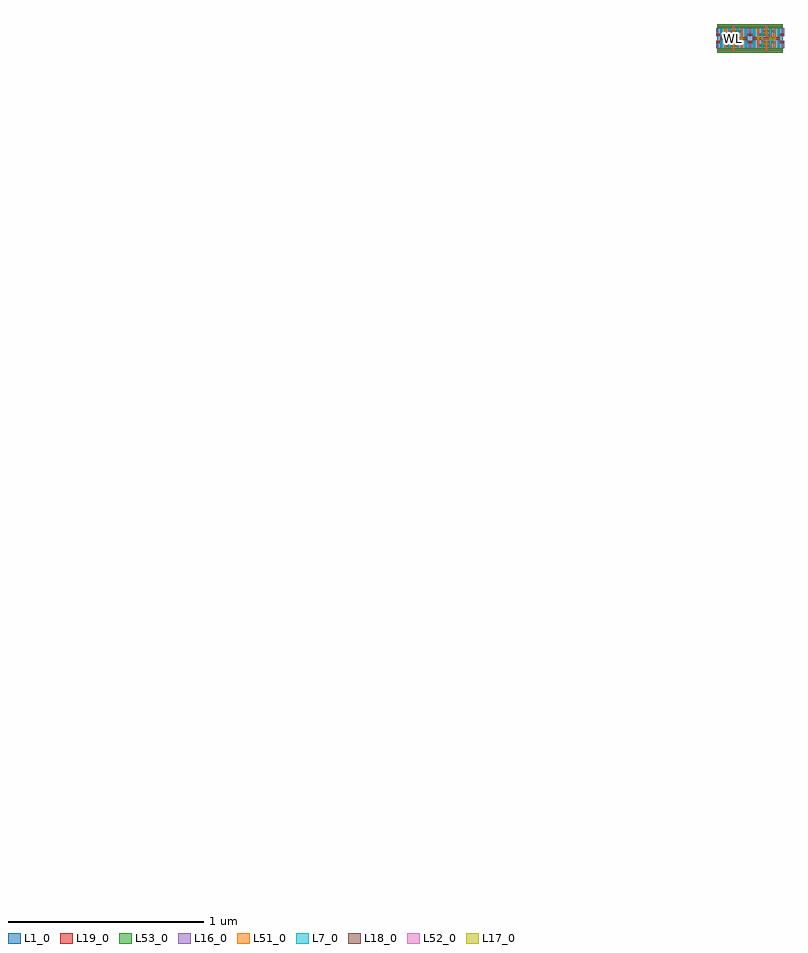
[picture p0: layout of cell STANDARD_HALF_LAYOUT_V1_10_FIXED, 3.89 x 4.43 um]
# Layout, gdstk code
import gdstk
lib = gdstk.Library(unit=1e-6, precision=1e-09)
def R(c, l, rs):  # rectangles x0, y0, x1, y1
    for r in rs: c.add(gdstk.rectangle(r[:2], r[2:], *l))
def A(c, l, x, y, w, h, nx, ny, dx, dy):  # array of equal rectangles
    R(c, l, [(x+i*dx, y+j*dy, x+i*dx+w, y+j*dy+h) for i in range(nx) for j in range(ny)])
def P(c, l, *ps):  # polygons
    for p in ps: c.add(gdstk.Polygon(p, *l))
L1_0 = (1, 0)
L7_0 = (7, 0)
L16_0 = (16, 0)
L17_0 = (17, 0)
L18_0 = (18, 0)
L19_0 = (19, 0)
L51_0 = (51, 0)
L52_0 = (52, 0)
L53_0 = (53, 0)

standard_half_layout_v1_ = lib.new_cell('STANDARD_HALF_LAYOUT_V1_10_FIXED')
A(standard_half_layout_v1_, L1_0, 0, 0, 0.042, 0.062, 8, 2, 0.042, 0.062)
P(standard_half_layout_v1_, L1_0, [(-2.637,-3.867),(-2.637,-3.867),(-2.637,-3.867),(-2.637,-3.867)],
  [(-3.548,-4.293),(-3.548,-4.293),(-3.548,-4.293),(-3.548,-4.293)],
  [(0.151,-0.013),(0.151,-0.013),(0.151,-0.013),(0.151,-0.013)],
  [(0.017,0.137),(0.017,0.137),(0.017,0.137),(0.017,0.137)],
  [(0.319,-0.013),(0.319,-0.013),(0.319,-0.013),(0.319,-0.013)],
  [(0.185,0.137),(0.185,0.137),(0.185,0.137),(0.185,0.137)])
A(standard_half_layout_v1_, L7_0, 0.015, 0.011, 0.012, 0.04, 8, 2, 0.042, 0.062)
A(standard_half_layout_v1_, L16_0, 0.015, 0.011, 0.012, 0.057, 3, 1, 0.021, 0)
A(standard_half_layout_v1_, L16_0, 0.183, 0.011, 0.012, 0.057, 3, 1, 0.021, 0)
A(standard_half_layout_v1_, L16_0, 0.099, 0.056, 0.012, 0.057, 3, 1, 0.021, 0)
A(standard_half_layout_v1_, L16_0, 0.267, 0.056, 0.012, 0.057, 3, 1, 0.021, 0)
R(standard_half_layout_v1_, L16_0, [(0.078,-0.006,0.09,0.051), (0.246,-0.006,0.258,0.051), (-0.006,0.011,0.006,0.051), (0.099,0.011,0.111,0.051), (0.12,0.011,0.132,0.051), (0.141,0.011,0.153,0.068), (0.162,0.011,0.174,0.051), (0.267,0.011,0.279,0.051), (0.288,0.011,0.3,0.051), (0.309,0.011,0.321,0.068), (0.33,0.011,0.342,0.051), (0.015,0.056,0.027,0.113), (0.183,0.056,0.195,0.113), (-0.006,0.073,0.006,0.113), (0.036,0.073,0.048,0.113), (0.057,0.073,0.069,0.113), (0.078,0.073,0.09,0.13), (0.162,0.073,0.174,0.113), (0.204,0.073,0.216,0.113), (0.225,0.073,0.237,0.113), (0.246,0.073,0.258,0.13), (0.33,0.073,0.342,0.113)])
R(standard_half_layout_v1_, L17_0, [(0.036,0.056,0.048,0.068), (0.057,0.056,0.069,0.068), (0.099,0.056,0.111,0.068), (0.12,0.056,0.132,0.068), (0.204,0.056,0.216,0.068), (0.225,0.056,0.237,0.068), (0.267,0.056,0.279,0.068), (0.288,0.056,0.3,0.068)])
A(standard_half_layout_v1_, L18_0, -0.005, 0.038, 0.01, 0.01, 3, 1, 0.063, 0)
A(standard_half_layout_v1_, L18_0, 0.163, 0.038, 0.01, 0.01, 3, 1, 0.063, 0)
A(standard_half_layout_v1_, L18_0, 0.037, 0.076, 0.01, 0.01, 3, 1, 0.063, 0)
A(standard_half_layout_v1_, L18_0, 0.205, 0.076, 0.01, 0.01, 3, 1, 0.063, 0)
R(standard_half_layout_v1_, L18_0, [(0.079,-0.005,0.089,0.005), (0.247,-0.005,0.257,0.005), (0.037,0.02,0.047,0.03), (0.1,0.02,0.11,0.03), (0.205,0.02,0.215,0.03), (0.268,0.02,0.278,0.03), (0.331,0.038,0.341,0.048), (0.015,0.056,0.027,0.068), (0.141,0.056,0.153,0.068), (0.183,0.056,0.195,0.068), (0.309,0.056,0.321,0.068), (-0.005,0.076,0.005,0.086), (0.058,0.094,0.068,0.104), (0.121,0.094,0.131,0.104), (0.226,0.094,0.236,0.104), (0.289,0.094,0.299,0.104), (0.079,0.119,0.089,0.129), (0.247,0.119,0.257,0.129)])
R(standard_half_layout_v1_, L19_0, [(0,-0.011,0.168,0.011), (0.168,-0.011,0.336,0.011), (0.036,0.02,0.111,0.03), (0.204,0.02,0.279,0.03), (-0.006,0.037,0.016,0.049), (0.057,0.037,0.132,0.049), (0.157,0.037,0.18,0.049), (0.225,0.037,0.3,0.049), (0.319,0.037,0.342,0.049), (0.015,0.056,0.153,0.068), (0.183,0.056,0.321,0.068), (-0.006,0.075,0.017,0.087), (0.036,0.075,0.111,0.087), (0.157,0.075,0.179,0.087), (0.204,0.075,0.279,0.087), (0.32,0.075,0.342,0.087), (0.057,0.094,0.132,0.104), (0.225,0.094,0.3,0.104), (0,0.113,0.168,0.135), (0.168,0.113,0.336,0.135)])
R(standard_half_layout_v1_, L51_0, [(0.078,-0.006,0.09,0.051), (0.246,-0.006,0.258,0.051), (0.036,0.011,0.048,0.068), (0.057,0.011,0.069,0.068), (0.099,0.011,0.111,0.051), (0.12,0.011,0.132,0.051), (0.204,0.011,0.216,0.068), (0.225,0.011,0.237,0.068), (0.267,0.011,0.279,0.051), (0.288,0.011,0.3,0.051), (0.099,0.056,0.111,0.113), (0.12,0.056,0.132,0.113), (0.267,0.056,0.279,0.113), (0.288,0.056,0.3,0.113), (0.036,0.073,0.048,0.113), (0.057,0.073,0.069,0.113), (0.078,0.073,0.09,0.13), (0.204,0.073,0.216,0.113), (0.225,0.073,0.237,0.113), (0.246,0.073,0.258,0.13)])
R(standard_half_layout_v1_, L52_0, [(0.079,-0.005,0.089,0.005), (0.247,-0.005,0.257,0.005), (0.037,0.02,0.047,0.03), (0.1,0.02,0.11,0.03), (0.205,0.02,0.215,0.03), (0.268,0.02,0.278,0.03), (0.058,0.038,0.068,0.048), (0.121,0.038,0.131,0.048), (0.226,0.038,0.236,0.048), (0.289,0.038,0.299,0.048), (0.037,0.076,0.047,0.086), (0.1,0.076,0.11,0.086), (0.205,0.076,0.215,0.086), (0.268,0.076,0.278,0.086), (0.058,0.094,0.068,0.104), (0.121,0.094,0.131,0.104), (0.226,0.094,0.236,0.104), (0.289,0.094,0.299,0.104), (0.079,0.119,0.089,0.129), (0.247,0.119,0.257,0.129)])
R(standard_half_layout_v1_, L53_0, [(0,-0.011,0.168,0.011), (0.168,-0.011,0.336,0.011), (0.036,0.019,0.111,0.031), (0.204,0.019,0.279,0.031), (0.057,0.037,0.132,0.049), (0.225,0.037,0.3,0.049), (0.036,0.075,0.111,0.087), (0.204,0.075,0.279,0.087), (0.057,0.093,0.132,0.105), (0.225,0.093,0.3,0.105), (0,0.113,0.168,0.135), (0.168,0.113,0.336,0.135)])
standard_half_layout_v1_.add(gdstk.Label('WL', (0.084,0.062), layer=19, texttype=0))
standard_half_layout_v1_.add(gdstk.Label('BLB', (0.168,0.043), layer=19, texttype=0))
standard_half_layout_v1_.add(gdstk.Label('BL', (0.005,0.043), layer=19, texttype=0))
standard_half_layout_v1_.add(gdstk.Label('VSS', (0.084,0), layer=19, texttype=0))
standard_half_layout_v1_.add(gdstk.Label('VDD', (0.084,0), layer=53, texttype=0))

lib.write_gds('STANDARD_HALF_LAYOUT_V1_10_FIXED.gds')
